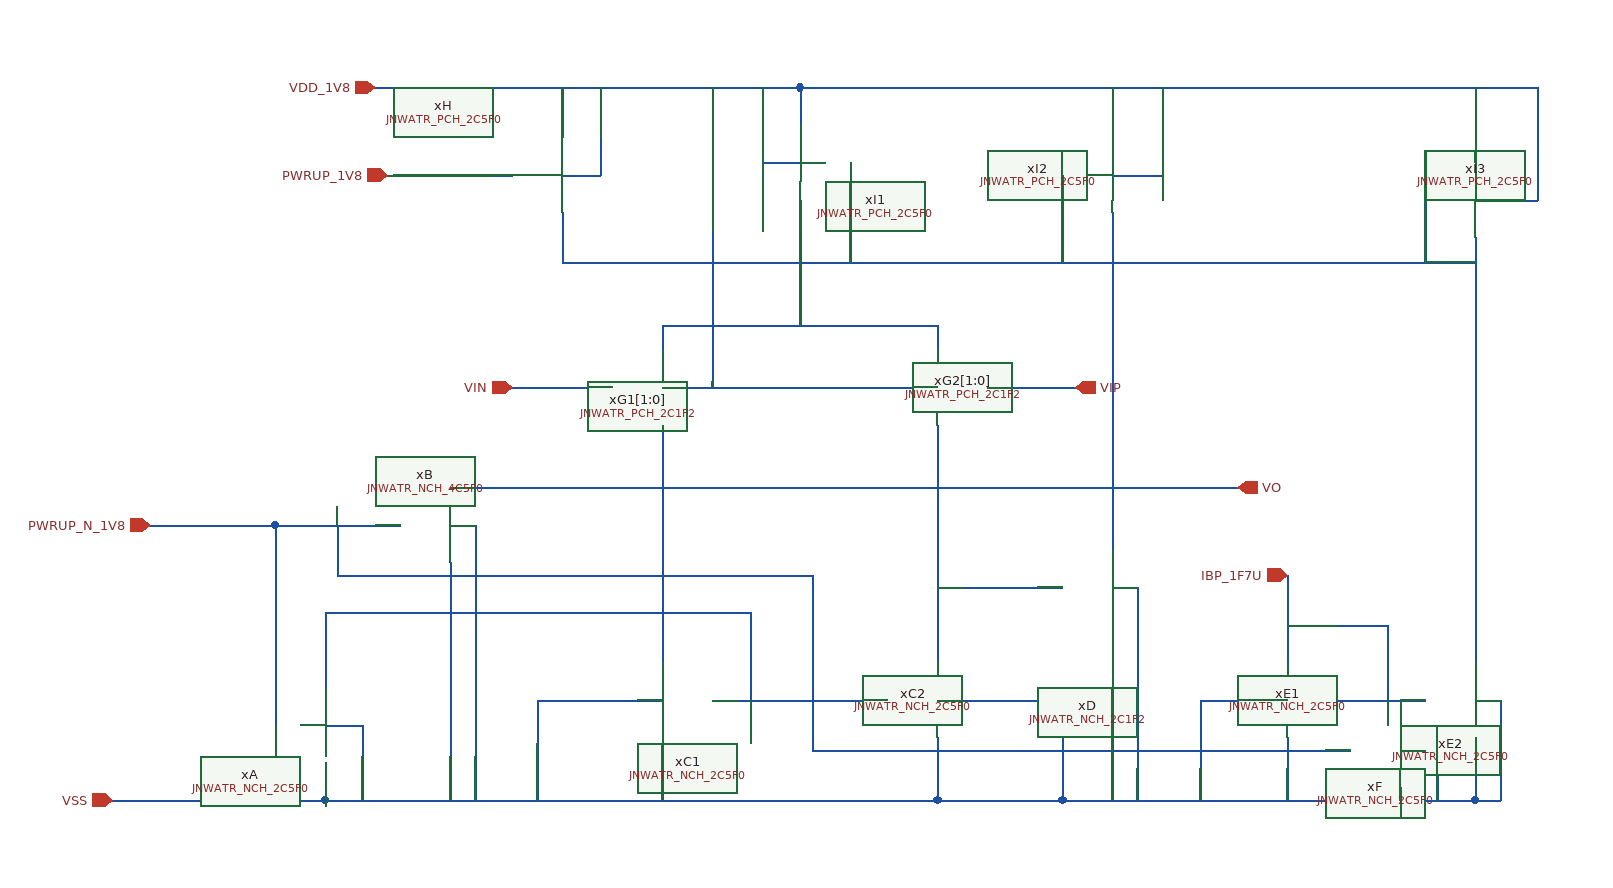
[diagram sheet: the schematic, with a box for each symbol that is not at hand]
v {xschem version=3.4.7 file_version=1.2}
G {}
K {}
V {}
S {}
E {}
N -120 20 20 20 {lab=#net1}
N -160 50 -160 100 {lab=VSS}
N 60 50 60 100 {lab=VSS}
N -90 -50 -90 20 {lab=#net1}
N -160 -120 -160 -10 {lab=#net1}
N -160 -50 -90 -50 {lab=#net1}
N 60 20 160 20 {lab=VSS}
N 60 -200 60 -10 {lab=#net2}
N -160 -200 -160 -120 {lab=#net1}
N -160 -280 -160 -260 {lab=#net3}
N -160 -280 60 -280 {lab=#net3}
N 60 -280 60 -260 {lab=#net3}
N -50 -310 -50 -280 {lab=#net3}
N -320 100 60 100 {lab=VSS}
N -260 20 -260 100 {lab=VSS}
N -260 20 -160 20 {lab=VSS}
N 160 20 160 100 {lab=VSS}
N 60 100 160 100 {lab=VSS}
N 160 100 250 100 {lab=VSS}
N 270 20 340 20 {lab=VSS}
N 270 20 270 100 {lab=VSS}
N 250 100 350 100 {lab=VSS}
N 340 50 340 100 {lab=VSS}
N 380 20 450 20 {lab=IBP_1F7U}
N 490 50 490 100 {lab=VSS}
N 350 100 490 100 {lab=VSS}
N 490 20 510 20 {lab=VSS}
N 510 20 510 100 {lab=VSS}
N 490 100 510 100 {lab=VSS}
N 420 -30 420 20 {lab=IBP_1F7U}
N 340 -80 340 -10 {lab=IBP_1F7U}
N 340 -40 420 -40 {lab=IBP_1F7U}
N 420 -40 420 -30 {lab=IBP_1F7U}
N 490 -230 490 -10 {lab=#net4}
N 490 -350 490 -230 {lab=#net4}
N 490 -380 540 -380 {lab=VDD_1V8}
N 490 -430 490 -410 {lab=VDD_1V8}
N 540 -430 540 -380 {lab=VDD_1V8}
N -200 -330 490 -330 {lab=#net4}
N -10 -410 -10 -340 {lab=#net4}
N -10 -340 -10 -330 {lab=#net4}
N 450 -380 450 -330 {lab=#net4}
N -50 -380 -50 -310 {lab=#net3}
N -50 -470 -50 -440 {lab=VDD_1V8}
N -50 -470 540 -470 {lab=VDD_1V8}
N 490 -470 490 -430 {lab=VDD_1V8}
N 540 -470 540 -430 {lab=VDD_1V8}
N -280 -230 -200 -230 {lab=VIN}
N 100 -230 170 -230 {lab=VIP}
N -160 -230 60 -230 {lab=VDD_1V8}
N -120 -470 -120 -230 {lab=VDD_1V8}
N -390 -470 -50 -470 {lab=VDD_1V8}
N -430 100 -320 100 {lab=VSS}
N 200 -470 200 -430 {lab=VDD_1V8}
N 160 -400 160 -330 {lab=#net4}
N 200 -400 240 -400 {lab=VDD_1V8}
N 240 -470 240 -400 {lab=VDD_1V8}
N -240 -370 -240 -330 {lab=#net4}
N -240 -330 -200 -330 {lab=#net4}
N -240 -470 -240 -430 {lab=VDD_1V8}
N -390 -400 -280 -400 {lab=PWRUP_1V8}
N -240 -400 -210 -400 {lab=VDD_1V8}
N -210 -470 -210 -400 {lab=VDD_1V8}
N 200 -370 200 -100 {lab=VO}
N 200 -150 300 -150 {lab=VO}
N 200 -40 200 100 {lab=VSS}
N 200 -70 220 -70 {lab=VSS}
N 220 -70 220 100 {lab=VSS}
N 60 -70 160 -70 {lab=#net2}
N -320 -50 -160 -50 {lab=#net1}
N -600 100 -430 100 {lab=VSS}
N -430 70 -430 100 {lab=VSS}
N -430 40 -400 40 {lab=VSS}
N -400 40 -400 100 {lab=VSS}
N -430 -50 -430 10 {lab=#net1}
N -430 -50 -320 -50 {lab=#net1}
N -470 -120 -470 40 {lab=PWRUP_N_1V8}
N -570 -120 -470 -120 {lab=PWRUP_N_1V8}
N -470 -120 -370 -120 {lab=PWRUP_N_1V8}
N -330 -150 200 -150 {lab=VO}
N -330 -90 -330 100 {lab=VSS}
N -330 -120 -310 -120 {lab=VSS}
N -310 -120 -310 100 {lab=VSS}
N -80 -410 -50 -410 {lab=VDD_1V8}
N -80 -470 -80 -410 {lab=VDD_1V8}
N 430 90 430 100 {lab=VSS}
N 430 60 460 60 {lab=VSS}
N 460 60 460 100 {lab=VSS}
N 430 20 430 30 {lab=IBP_1F7U}
N -40 60 390 60 {lab=PWRUP_N_1V8}
N -40 -80 -40 60 {lab=PWRUP_N_1V8}
N -420 -80 -40 -80 {lab=PWRUP_N_1V8}
N -420 -120 -420 -80 {lab=PWRUP_N_1V8}
C {JNW_ATR_SKY130A/JNWATR_NCH_2C5F0.sym} 20 20 0 0 {name=xC2}
C {JNW_ATR_SKY130A/JNWATR_NCH_2C5F0.sym} -120 20 0 1 {name=xC1}
C {JNW_ATR_SKY130A/JNWATR_PCH_2C1F2.sym} 100 -230 0 1 {name=xG2[1:0]
}
C {JNW_ATR_SKY130A/JNWATR_PCH_2C1F2.sym} -200 -230 0 0 {name=xG1[1:0]}
C {JNW_ATR_SKY130A/JNWATR_NCH_2C5F0.sym} 380 20 0 1 {name=xE1}
C {JNW_ATR_SKY130A/JNWATR_NCH_2C5F0.sym} 450 20 0 0 {name=xE2}
C {JNW_ATR_SKY130A/JNWATR_PCH_2C5F0.sym} 450 -380 0 0 {name=xI3}
C {JNW_ATR_SKY130A/JNWATR_PCH_2C5F0.sym} -10 -410 0 1 {name=xI1 }
C {devices/ipin.sym} -280 -230 0 0 {name=p1 lab=VIN
}
C {devices/ipin.sym} 170 -230 0 1 {name=p2 lab=VIP}
C {devices/ipin.sym} -600 100 0 0 {name=p3 lab=VSS}
C {devices/ipin.sym} -390 -470 0 0 {name=p4 lab=VDD_1V8
}
C {JNW_ATR_SKY130A/JNWATR_PCH_2C5F0.sym} 160 -400 0 0 {name=xI2}
C {JNW_ATR_SKY130A/JNWATR_PCH_2C5F0.sym} -280 -400 0 0 {name=xH }
C {devices/opin.sym} 300 -150 0 0 {name=p5 lab=VO
}
C {JNW_ATR_SKY130A/JNWATR_NCH_2C1F2.sym} 160 -70 0 0 {name=xD}
C {JNW_ATR_SKY130A/JNWATR_NCH_2C5F0.sym} -470 40 0 0 {name=xA }
C {devices/ipin.sym} -570 -120 0 0 {name=p6 lab=PWRUP_N_1V8
}
C {devices/ipin.sym} -380 -400 0 0 {name=p7 lab=PWRUP_1V8
}
C {JNW_ATR_SKY130A/JNWATR_NCH_4C5F0.sym} -370 -120 0 0 {name=xB }
C {devices/ipin.sym} 340 -80 0 0 {name=p8 lab=IBP_1F7U}
C {JNW_ATR_SKY130A/JNWATR_NCH_2C5F0.sym} 390 60 0 0 {name=xF}
